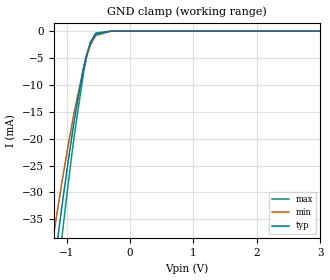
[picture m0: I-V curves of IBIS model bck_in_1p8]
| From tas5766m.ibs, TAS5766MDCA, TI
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|   bck_in_1p8 Model
[Model]   bck_in_1p8
Model_type   Input
Vinl = 0.54
Vinh = 1.26
|   typ   min   max
C_comp   1.51429pF   1.436730pF   1.542051pF
[Voltage Range]   1.8   1.65   1.95
[Temperature Range]   27   105   -25
[Power Clamp Reference]   1.8   1.65   1.95
[GND Clamp Reference]   -0   -0   -0
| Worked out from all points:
|   GND clamp passes 1 mA (typ) near -0.57 V on its own axis
[GND Clamp]
|   Voltage   I(typ)   I(min)   I(max)
-1.8V     -103.9mA   -86.97mA   -120.1mA
-1.29V    -52.65mA   -44.58mA   -61.57mA
-1.182V   -42.49mA   -36.24mA   -49.8mA
-1.074V   -32.76mA   -28.25mA   -38.44mA
-974.7mV  -24.27mA   -21.3mA    -28.44mA
-880.4mV  -16.79mA   -15.16mA   -19.63mA
-734.2mV  -6.985mA   -6.98mA    -7.926mA
-686.2mV  -4.486mA   -4.819mA   -4.945mA
-622.6mV  -2.125mA   -2.565mA   -2.05mA
-539.6mV  -557.4uA   -827.2uA   -348.4uA
-296.6mV  -421.6nA   -3.207uA   -166.4nA
3.6V      0A         0A         0A
[POWER Clamp]
|   Voltage   I(typ)   I(min)   I(max)
-1.8V     0A         0A         0A
0V        0A         0A         0A
3.6V      0A         0A         0A
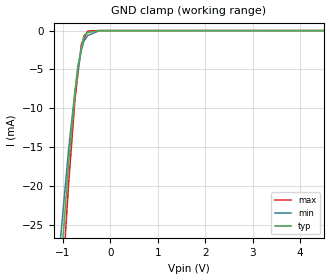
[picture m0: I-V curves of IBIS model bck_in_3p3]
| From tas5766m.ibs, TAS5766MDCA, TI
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|   bck_in_3p3 Model
[Model]   bck_in_3p3
Model_type   Input
Vinl = 0.99
Vinh = 2.31
|   typ   min   max
C_comp   1.426525pF   1.374530pF   1.444284pF
[Voltage Range]   3.3   3   3.6
[Temperature Range]   27   105   -25
[Power Clamp Reference]   3.3   3   3.6
[GND Clamp Reference]   -0   -0   -0
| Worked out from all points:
|   GND clamp passes 1 mA (typ) near -0.57 V on its own axis
[GND Clamp]
|   Voltage   I(typ)   I(min)   I(max)
-3.3V     -526.5mA   -489.6mA   -552.8mA
-1.223V   -46.27mA   -39.34mA   -54.17mA
-1.139V   -38.52mA   -32.98mA   -45.18mA
-1.078V   -33.07mA   -28.51mA   -38.81mA
-882.5mV  -17.07mA   -15.34mA   -19.81mA
-746.7mV  -8.048mA   -7.686mA   -8.786mA
-689.8mV  -4.65mA    -5.27mA    -5.807mA
-610.8mV  -2.252mA   -2.464mA   -1.67mA
-557.7mV  -638.8uA   -1.348mA   -1.038mA
-475mV    -252.8uA   -630.3uA   -54.69uA
-230.4mV  -11.43uA   -497.9nA   -215.4nA
6.6V      0A         0A         0A
[POWER Clamp]
|   Voltage   I(typ)   I(min)   I(max)
-3.3V     0A         0A         0A
0V        0A         0A         0A
6.6V      0A         0A         0A
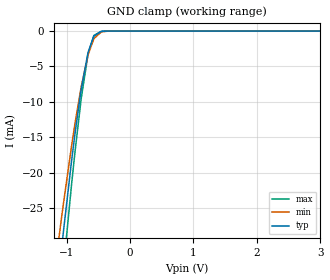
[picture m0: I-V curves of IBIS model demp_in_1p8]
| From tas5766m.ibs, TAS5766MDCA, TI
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|   demp_in_1p8 Model
[Model]   demp_in_1p8
Model_type   Input
Vinl = 0.54
Vinh = 1.26
|   typ   min   max
C_comp   1.023635pF   1.008986pF   1.039026pF
[Voltage Range]   1.8   1.65   1.95
[Temperature Range]   27   105   -25
[Power Clamp Reference]   1.8   1.65   1.95
[GND Clamp Reference]   -0   -0   -0
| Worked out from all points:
|   GND clamp passes 1 mA (typ) near -0.58 V on its own axis
[GND Clamp]
|   Voltage   I(typ)   I(min)   I(max)
-1.8V     -97.74mA   -81.51mA   -113.4mA
-1.238V   -44.53mA   -37.64mA   -52.44mA
-1.093V   -31.94mA   -27.34mA   -37.74mA
-1.044V   -27.93mA   -24.07mA   -33.03mA
-919.8mV  -18.28mA   -16.17mA   -21.6mA
-865.8mV  -14.42mA   -13.01mA   -17mA
-768.6mV  -8.212mA   -7.858mA   -9.529mA
-660.6mV  -2.999mA   -3.364mA   -3.244mA
-568.8mV  -690.4uA   -1.063mA   -614.2uA
-450mV    -38.26uA   -112.2uA   -20.73uA
-347.4mV  -1.66uA    -10.08uA   -447nA
3.6V      0A         0A         0A
[POWER Clamp]
|   Voltage   I(typ)   I(min)   I(max)
-1.8V     0A         0A         0A
0V        0A         0A         0A
3.6V      0A         0A         0A
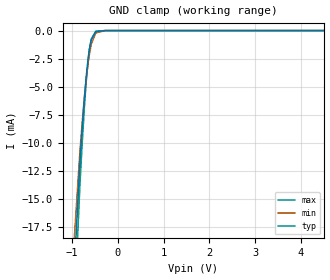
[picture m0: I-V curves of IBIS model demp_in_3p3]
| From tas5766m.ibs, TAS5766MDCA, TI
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|   demp_in_3p3 Model
[Model]   demp_in_3p3
Model_type   Input
Vinl = 0.99
Vinh = 2.31
|   typ   min   max
C_comp   0.96423pF   0.946438pF   0.978689pF
[Voltage Range]   3.3   3   3.6
[Temperature Range]   27   105   -25
[Power Clamp Reference]   3.3   3   3.6
[GND Clamp Reference]   -0   -0   -0
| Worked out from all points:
|   GND clamp passes 1 mA (typ) near -0.59 V on its own axis
[GND Clamp]
|   Voltage   I(typ)   I(min)   I(max)
-3.3V     -526.2mA   -489.3mA   -552.6mA
-1.152V   -36.95mA   -31.43mA   -43.61mA
-825mV    -11.69mA   -10.75mA   -13.71mA
-775.5mV  -8.615mA   -8.195mA   -10.02mA
-726mV    -5.891mA   -5.897mA   -6.724mA
-686.4mV  -4.029mA   -4.285mA   -4.478mA
-646.8mV  -2.514mA   -2.918mA   -2.669mA
-617.1mV  -1.636mA   -2.075mA   -1.648mA
-577.5mV  -819uA     -1.212mA   -747.8uA
-478.5mV  -82.94uA   -205.2uA   -52.14uA
-270.6mV  -108.6nA   -1.321uA   -6.009nA
6.6V      0A         0A         0A
[POWER Clamp]
|   Voltage   I(typ)   I(min)   I(max)
-3.3V     0A         0A         0A
0V        0A         0A         0A
6.6V      0A         0A         0A
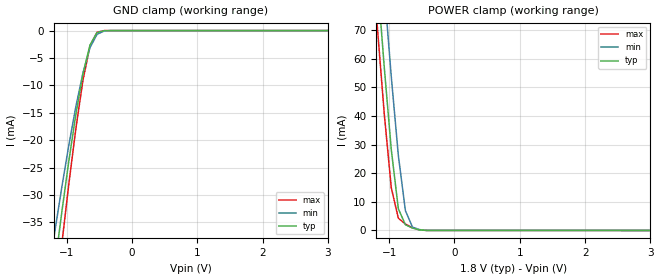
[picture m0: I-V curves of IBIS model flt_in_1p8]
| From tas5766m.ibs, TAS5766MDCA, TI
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|   flt_in_1p8 Model
[Model]   flt_in_1p8
Model_type   Input
Vinl = 0.54
Vinh = 1.26
|   typ   min   max
C_comp   1.492329pF   1.472260pF   1.515772pF
[Voltage Range]   1.8   1.65   1.95
[Temperature Range]   27   105   -25
[Power Clamp Reference]   1.8   1.65   1.95
[GND Clamp Reference]   -0   -0   -0
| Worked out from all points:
|   GND clamp passes 1 mA (typ) near -0.56 V on its own axis
|   POWER clamp passes 1 mA (typ) near -0.66 V on its own axis
[GND Clamp]
|   Voltage   I(typ)   I(min)   I(max)
-1.8V     -105.9mA   -88.79mA   -122.2mA
-1.182V   -43.15mA   -36.82mA   -50.61mA
-1.074V   -33.22mA   -28.66mA   -39.05mA
-966.5mV  -23.87mA   -20.97mA   -28.07mA
-858.5mV  -15.31mA   -13.91mA   -17.93mA
-750.5mV  -7.963mA   -7.777mA   -9.142mA
-642.5mV  -2.664mA   -3.129mA   -2.804mA
-534.5mV  -378.4uA   -687.8uA   -300.4uA
-426.5mV  -22.54uA   -76.81uA   -10.61uA
-318.5mV  -722.7nA   -5.54uA    -151.4nA
3.6V      0A         0A         0A
[POWER Clamp]
|   Voltage   I(typ)   I(min)   I(max)
-1.8V     283.3mA    311.2mA    266.4mA
-1.182V   88.62mA    116.6mA    71.64mA
-1.074V   57.01mA    84.37mA    40.75mA
-966.5mV  28.23mA    53.67mA    14.9mA
-858.5mV  7.578mA    26.2mA     4.28mA
-750.5mV  2.019mA    6.936mA    2.253mA
-642.5mV  840.3uA    1.18mA     932.9uA
-534.5mV  214uA      297.3uA    193.5uA
-426.5mV  21.46uA    49.86uA    12.56uA
3.6V      0A         0A         0A
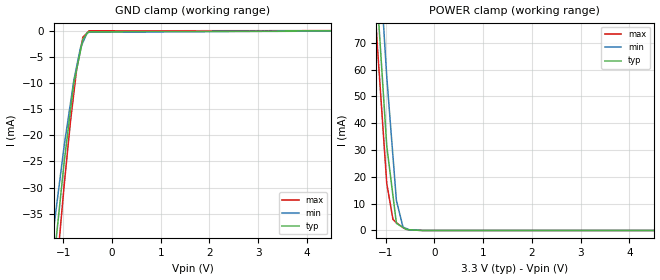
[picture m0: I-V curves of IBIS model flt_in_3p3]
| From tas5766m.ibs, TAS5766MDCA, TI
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|   flt_in_3p3 Model
[Model]   flt_in_3p3
Model_type   Input
Vinl = 0.99
Vinh = 2.31
|   typ   min   max
C_comp   1.387421pF   1.361818pF   1.403792pF
[Voltage Range]   3.3   3   3.6
[Temperature Range]   27   105   -25
[Power Clamp Reference]   3.3   3   3.6
[GND Clamp Reference]   -0   -0   -0
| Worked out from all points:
|   GND clamp passes 1 mA (typ) near -0.58 V on its own axis
|   POWER clamp passes 1 mA (typ) near -0.63 V on its own axis
[GND Clamp]
|   Voltage   I(typ)   I(min)   I(max)
-3.3V     -527.4mA   -490.8mA   -553.6mA
-1.376V   -61.94mA   -52.32mA   -72.28mA
-1.178V   -42.72mA   -36.47mA   -50.11mA
-979.8mV  -24.99mA   -21.89mA   -29.39mA
-852.3mV  -15.29mA   -13.87mA   -17.38mA
-781.8mV  -9.934mA   -9.438mA   -11.84mA
-724.7mV  -7.371mA   -6.834mA   -7.349mA
-646.4mV  -3.858mA   -3.264mA   -3.625mA
-597.2mV  -1.648mA   -2.24mA    -1.282mA
-511mV    -520.4uA   -448.6uA   -446.7uA
-469.6mV  -219.9uA   -318.6uA   -45.44uA
6.6V      0A         0A         0A
[POWER Clamp]
|   Voltage   I(typ)   I(min)   I(max)
-3.3V     774.1mA    800.5mA    758.1mA
-1.376V   148.1mA    176.3mA    130.9mA
-1.178V   87.23mA    115.2mA    70.27mA
-979.8mV  31.54mA    57.35mA    17.54mA
-852.3mV  12.94mA    27.6mA     4.106mA
-781.8mV  2.67mA     11.17mA    2.884mA
-646.4mV  1.145mA    1.248mA    1.065mA
-583.8mV  440.6uA    769.8uA    491.1uA
-511mV    227.7uA    213.4uA    205.2uA
-240.2mV  18.36uA    663.8nA    484nA
6.6V      0A         0A         0A
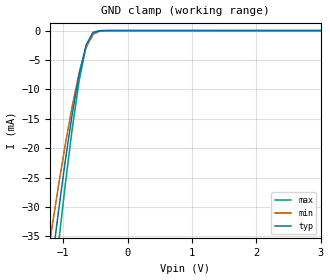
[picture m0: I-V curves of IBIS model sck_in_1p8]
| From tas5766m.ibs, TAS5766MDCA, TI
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|   sck_in_1p8 Model
[Model]   sck_in_1p8
Model_type   Input
Vinl = 0.54
Vinh = 1.26
|   typ   min   max
C_comp   1.071750pF   1.051762pF   1.095949pF
[Voltage Range]   1.8   1.65   1.95
[Temperature Range]   27   105   -25
[Power Clamp Reference]   1.8   1.65   1.95
[GND Clamp Reference]   -0   -0   -0
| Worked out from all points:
|   GND clamp passes 1 mA (typ) near -0.57 V on its own axis
[GND Clamp]
|   Voltage   I(typ)   I(min)   I(max)
-1.8V     -98.84mA   -82.48mA   -114.6mA
-1.182V   -40.15mA   -34.09mA   -47.29mA
-1.074V   -30.87mA   -26.51mA   -36.44mA
-966.5mV  -22.14mA   -19.37mA   -26.15mA
-858.5mV  -14.17mA   -12.82mA   -16.66mA
-750.5mV  -7.34mA    -7.15mA    -8.456mA
-642.5mV  -2.44mA    -2.864mA   -2.573mA
-534.5mV  -344.3uA   -626.2uA   -273.2uA
-426.5mV  -20.47uA   -69.77uA   -9.634uA
-318.5mV  -657.5nA   -5.032uA   -138.7nA
3.6V      0A         0A         0A
[POWER Clamp]
|   Voltage   I(typ)   I(min)   I(max)
-1.8V     0A         0A         0A
0V        0A         0A         0A
3.6V      0A         0A         0A
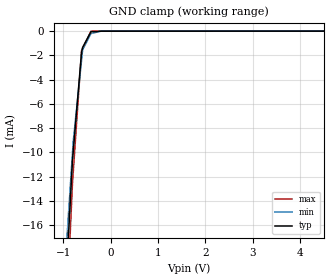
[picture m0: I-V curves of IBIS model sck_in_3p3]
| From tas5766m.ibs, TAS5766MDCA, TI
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|   sck_in_3p3 Model
[Model]   sck_in_3p3
Model_type   Input
Vinl = 0.99
Vinh = 2.31
|   typ   min   max
C_comp   1.009791pF   0.990329pF   1.034833pF
[Voltage Range]   3.3   3   3.6
[Temperature Range]   27   105   -25
[Power Clamp Reference]   3.3   3   3.6
[GND Clamp Reference]   -0   -0   -0
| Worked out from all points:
|   GND clamp passes 1 mA (typ) near -0.54 V on its own axis
[GND Clamp]
|   Voltage   I(typ)   I(min)   I(max)
-3.3V     -526.2mA   -489.4mA   -552.7mA
-1.384V   -58.51mA   -49.12mA   -68.56mA
-1.208V   -42.45mA   -36.01mA   -49.95mA
-1.186V   -40.51mA   -34.34mA   -47.72mA
-1.01V    -25.63mA   -22.28mA   -30.25mA
-806.5mV  -10.7mA    -10.07mA   -12.62mA
-789.9mV  -9.929mA   -9.096mA   -11.67mA
-614.3mV  -1.741mA   -2.396mA   -1.618mA
-591.9mV  -1.349mA   -1.541mA   -1.436mA
-416.3mV  -55.3uA    -203.5uA   -6.682uA
-195.9mV  -8.324uA   -155.8nA   -2.963uA
6.6V      0A         0A         0A
[POWER Clamp]
|   Voltage   I(typ)   I(min)   I(max)
-3.3V     0A         0A         0A
0V        0A         0A         0A
6.6V      0A         0A         0A
